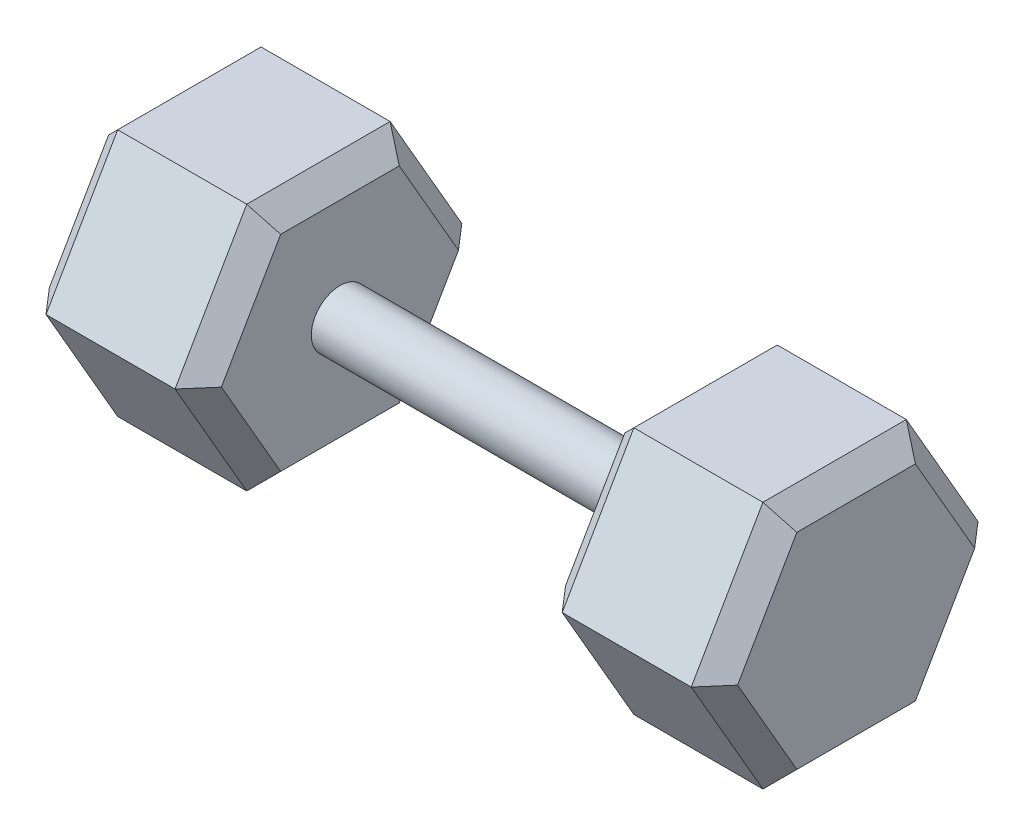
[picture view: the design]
ISO-10303-21;
HEADER;
FILE_DESCRIPTION(('STEP AP214'),'2;1');
FILE_NAME('part.step','',(''),(''),'','','');
FILE_SCHEMA(('AUTOMOTIVE_DESIGN { 1 0 10303 214 1 1 1 1 }'));
ENDSEC;
DATA;
#1=APPLICATION_CONTEXT('core data for automotive mechanical design processes');
#2=APPLICATION_PROTOCOL_DEFINITION('international standard','automotive_design',2000,#1);
#3=PRODUCT_CONTEXT('',#1,'mechanical');
#4=PRODUCT('Part','Part','',(#3));
#5=PRODUCT_RELATED_PRODUCT_CATEGORY('part','',(#4));
#6=PRODUCT_DEFINITION_FORMATION('','',#4);
#7=PRODUCT_DEFINITION_CONTEXT('part definition',#1,'design');
#8=PRODUCT_DEFINITION('design','',#6,#7);
#9=PRODUCT_DEFINITION_SHAPE('','',#8);
#10=(LENGTH_UNIT() NAMED_UNIT(*) SI_UNIT(.MILLI.,.METRE.));
#11=(NAMED_UNIT(*) PLANE_ANGLE_UNIT() SI_UNIT($,.RADIAN.));
#12=(NAMED_UNIT(*) SI_UNIT($,.STERADIAN.) SOLID_ANGLE_UNIT());
#13=UNCERTAINTY_MEASURE_WITH_UNIT(LENGTH_MEASURE(1.E-05),#10,'distance_accuracy_value','');
#14=(GEOMETRIC_REPRESENTATION_CONTEXT(3) GLOBAL_UNCERTAINTY_ASSIGNED_CONTEXT((#13)) GLOBAL_UNIT_ASSIGNED_CONTEXT((#10,
#11,#12)) REPRESENTATION_CONTEXT('',''));
#15=CARTESIAN_POINT('',(0.,0.,0.));
#16=DIRECTION('',(0.,0.,1.));
#17=DIRECTION('',(1.,0.,0.));
#18=AXIS2_PLACEMENT_3D('',#15,#16,#17);
#19=CARTESIAN_POINT('',(76.2,-109.985226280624,0.));
#20=DIRECTION('',(-1.,0.,0.));
#21=DIRECTION('',(0.,0.,1.));
#22=AXIS2_PLACEMENT_3D('',#19,#20,#21);
#23=PLANE('',#22);
#24=DIRECTION('',(0.,-0.866025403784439,-0.5));
#25=VECTOR('',#24,1.);
#26=CARTESIAN_POINT('',(76.2,-105.222726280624,-8.24889197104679));
#27=LINE('',#26,#25);
#28=CARTESIAN_POINT('',(76.2,0.,52.5014773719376));
#29=VERTEX_POINT('',#28);
#30=CARTESIAN_POINT('',(76.2,-45.4676131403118,26.2507386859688));
#31=VERTEX_POINT('',#30);
#32=EDGE_CURVE('E47',#29,#31,#27,.T.);
#33=ORIENTED_EDGE('',*,*,#32,.T.);
#34=DIRECTION('',(0.,0.,-1.));
#35=VECTOR('',#34,1.);
#36=CARTESIAN_POINT('',(76.2,-45.4676131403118,0.));
#37=LINE('',#36,#35);
#38=CARTESIAN_POINT('',(76.2,-45.4676131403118,-26.2507386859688));
#39=VERTEX_POINT('',#38);
#40=EDGE_CURVE('E40',#31,#39,#37,.T.);
#41=ORIENTED_EDGE('',*,*,#40,.T.);
#42=DIRECTION('',(0.,0.866025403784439,-0.5));
#43=VECTOR('',#42,1.);
#44=CARTESIAN_POINT('',(76.2,-105.222726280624,8.24889197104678));
#45=LINE('',#44,#43);
#46=CARTESIAN_POINT('',(76.2,0.,-52.5014773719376));
#47=VERTEX_POINT('',#46);
#48=EDGE_CURVE('E375',#39,#47,#45,.T.);
#49=ORIENTED_EDGE('',*,*,#48,.T.);
#50=DIRECTION('',(0.,0.866025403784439,0.5));
#51=VECTOR('',#50,1.);
#52=CARTESIAN_POINT('',(76.2,-59.7551131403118,-87.0011080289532));
#53=LINE('',#52,#51);
#54=CARTESIAN_POINT('',(76.2,45.4676131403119,-26.2507386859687));
#55=VERTEX_POINT('',#54);
#56=EDGE_CURVE('E377',#47,#55,#53,.T.);
#57=ORIENTED_EDGE('',*,*,#56,.T.);
#58=DIRECTION('',(0.,0.,1.));
#59=VECTOR('',#58,1.);
#60=CARTESIAN_POINT('',(76.2,45.4676131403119,0.));
#61=LINE('',#60,#59);
#62=CARTESIAN_POINT('',(76.2,45.4676131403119,26.2507386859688));
#63=VERTEX_POINT('',#62);
#64=EDGE_CURVE('E379',#55,#63,#61,.T.);
#65=ORIENTED_EDGE('',*,*,#64,.T.);
#66=DIRECTION('',(0.,-0.866025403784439,0.5));
#67=VECTOR('',#66,1.);
#68=CARTESIAN_POINT('',(76.2,-59.7551131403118,87.0011080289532));
#69=LINE('',#68,#67);
#70=EDGE_CURVE('E52',#63,#29,#69,.T.);
#71=ORIENTED_EDGE('',*,*,#70,.T.);
#72=EDGE_LOOP('',(#33,#41,#49,#57,#65,#71));
#73=FACE_BOUND('',#72,.T.);
#74=CARTESIAN_POINT('',(76.2,0.,0.));
#75=DIRECTION('',(-1.,0.,0.));
#76=DIRECTION('',(0.,0.,1.));
#77=AXIS2_PLACEMENT_3D('',#74,#75,#76);
#78=CIRCLE('',#77,12.6913169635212);
#79=CARTESIAN_POINT('',(76.2,0.,12.6913169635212));
#80=VERTEX_POINT('',#79);
#81=EDGE_CURVE('E11',#80,#80,#78,.F.);
#82=ORIENTED_EDGE('',*,*,#81,.F.);
#83=EDGE_LOOP('',(#82));
#84=FACE_BOUND('',#83,.T.);
#85=ADVANCED_FACE('F32',(#73,#84),#23,.F.);
#86=CARTESIAN_POINT('',(76.2,-54.9926131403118,-31.75));
#87=DIRECTION('',(0.,0.5,0.866025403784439));
#88=DIRECTION('',(0.,-0.866025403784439,0.5));
#89=AXIS2_PLACEMENT_3D('',#86,#87,#88);
#90=PLANE('',#89);
#91=DIRECTION('',(-1.,0.,0.));
#92=VECTOR('',#91,1.);
#93=CARTESIAN_POINT('',(76.2,-54.9926131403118,-31.75));
#94=LINE('',#93,#92);
#95=CARTESIAN_POINT('',(66.675,-54.9926131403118,-31.75));
#96=VERTEX_POINT('',#95);
#97=CARTESIAN_POINT('',(9.52500000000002,-54.9926131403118,-31.75));
#98=VERTEX_POINT('',#97);
#99=EDGE_CURVE('E317',#96,#98,#94,.T.);
#100=ORIENTED_EDGE('',*,*,#99,.T.);
#101=DIRECTION('',(0.,0.866025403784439,-0.5));
#102=VECTOR('',#101,1.);
#103=CARTESIAN_POINT('',(9.52499999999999,0.,-63.5));
#104=LINE('',#103,#102);
#105=CARTESIAN_POINT('',(9.52500000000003,0.,-63.5));
#106=VERTEX_POINT('',#105);
#107=EDGE_CURVE('E373',#98,#106,#104,.T.);
#108=ORIENTED_EDGE('',*,*,#107,.T.);
#109=DIRECTION('',(-1.,0.,0.));
#110=VECTOR('',#109,1.);
#111=CARTESIAN_POINT('',(76.2,0.,-63.5));
#112=LINE('',#111,#110);
#113=CARTESIAN_POINT('',(66.675,0.,-63.5));
#114=VERTEX_POINT('',#113);
#115=EDGE_CURVE('E333',#114,#106,#112,.T.);
#116=ORIENTED_EDGE('',*,*,#115,.F.);
#117=DIRECTION('',(0.,-0.866025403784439,0.5));
#118=VECTOR('',#117,1.);
#119=CARTESIAN_POINT('',(66.675,-54.9926131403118,-31.75));
#120=LINE('',#119,#118);
#121=EDGE_CURVE('E371',#114,#96,#120,.T.);
#122=ORIENTED_EDGE('',*,*,#121,.T.);
#123=EDGE_LOOP('',(#100,#108,#116,#122));
#124=FACE_BOUND('',#123,.T.);
#125=ADVANCED_FACE('F474',(#124),#90,.F.);
#126=CARTESIAN_POINT('',(76.2,0.,-63.5));
#127=DIRECTION('',(0.,-0.5,0.866025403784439));
#128=DIRECTION('',(0.,-0.866025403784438,-0.5));
#129=AXIS2_PLACEMENT_3D('',#126,#127,#128);
#130=PLANE('',#129);
#131=ORIENTED_EDGE('',*,*,#115,.T.);
#132=DIRECTION('',(0.,0.866025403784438,0.5));
#133=VECTOR('',#132,1.);
#134=CARTESIAN_POINT('',(9.52499999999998,54.9926131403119,-31.75));
#135=LINE('',#134,#133);
#136=CARTESIAN_POINT('',(9.52500000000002,54.9926131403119,-31.75));
#137=VERTEX_POINT('',#136);
#138=EDGE_CURVE('E338',#106,#137,#135,.T.);
#139=ORIENTED_EDGE('',*,*,#138,.T.);
#140=DIRECTION('',(-1.,0.,0.));
#141=VECTOR('',#140,1.);
#142=CARTESIAN_POINT('',(76.2,54.9926131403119,-31.75));
#143=LINE('',#142,#141);
#144=CARTESIAN_POINT('',(66.675,54.9926131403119,-31.75));
#145=VERTEX_POINT('',#144);
#146=EDGE_CURVE('E330',#145,#137,#143,.T.);
#147=ORIENTED_EDGE('',*,*,#146,.F.);
#148=DIRECTION('',(0.,-0.866025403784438,-0.5));
#149=VECTOR('',#148,1.);
#150=CARTESIAN_POINT('',(66.675,0.,-63.5));
#151=LINE('',#150,#149);
#152=EDGE_CURVE('E336',#145,#114,#151,.T.);
#153=ORIENTED_EDGE('',*,*,#152,.T.);
#154=EDGE_LOOP('',(#131,#139,#147,#153));
#155=FACE_BOUND('',#154,.T.);
#156=ADVANCED_FACE('F426',(#155),#130,.F.);
#157=CARTESIAN_POINT('',(76.2,54.9926131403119,-31.75));
#158=DIRECTION('',(0.,-1.,0.));
#159=DIRECTION('',(0.,0.,-1.));
#160=AXIS2_PLACEMENT_3D('',#157,#158,#159);
#161=PLANE('',#160);
#162=ORIENTED_EDGE('',*,*,#146,.T.);
#163=DIRECTION('',(0.,0.,1.));
#164=VECTOR('',#163,1.);
#165=CARTESIAN_POINT('',(9.52499999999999,54.9926131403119,31.75));
#166=LINE('',#165,#164);
#167=CARTESIAN_POINT('',(9.52500000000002,54.9926131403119,31.75));
#168=VERTEX_POINT('',#167);
#169=EDGE_CURVE('E356',#137,#168,#166,.T.);
#170=ORIENTED_EDGE('',*,*,#169,.T.);
#171=DIRECTION('',(-1.,0.,0.));
#172=VECTOR('',#171,1.);
#173=CARTESIAN_POINT('',(76.2,54.9926131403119,31.75));
#174=LINE('',#173,#172);
#175=CARTESIAN_POINT('',(66.675,54.9926131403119,31.75));
#176=VERTEX_POINT('',#175);
#177=EDGE_CURVE('E327',#176,#168,#174,.T.);
#178=ORIENTED_EDGE('',*,*,#177,.F.);
#179=DIRECTION('',(0.,0.,-1.));
#180=VECTOR('',#179,1.);
#181=CARTESIAN_POINT('',(66.675,54.9926131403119,-31.75));
#182=LINE('',#181,#180);
#183=EDGE_CURVE('E354',#176,#145,#182,.T.);
#184=ORIENTED_EDGE('',*,*,#183,.T.);
#185=EDGE_LOOP('',(#162,#170,#178,#184));
#186=FACE_BOUND('',#185,.T.);
#187=ADVANCED_FACE('F424',(#186),#161,.F.);
#188=CARTESIAN_POINT('',(76.2,54.9926131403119,31.75));
#189=DIRECTION('',(0.,-0.5,-0.866025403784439));
#190=DIRECTION('',(0.,0.866025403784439,-0.5));
#191=AXIS2_PLACEMENT_3D('',#188,#189,#190);
#192=PLANE('',#191);
#193=ORIENTED_EDGE('',*,*,#177,.T.);
#194=DIRECTION('',(0.,-0.866025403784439,0.5));
#195=VECTOR('',#194,1.);
#196=CARTESIAN_POINT('',(9.52499999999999,0.,63.5));
#197=LINE('',#196,#195);
#198=CARTESIAN_POINT('',(9.52500000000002,0.,63.5));
#199=VERTEX_POINT('',#198);
#200=EDGE_CURVE('E360',#168,#199,#197,.T.);
#201=ORIENTED_EDGE('',*,*,#200,.T.);
#202=DIRECTION('',(-1.,0.,0.));
#203=VECTOR('',#202,1.);
#204=CARTESIAN_POINT('',(76.2,0.,63.5));
#205=LINE('',#204,#203);
#206=CARTESIAN_POINT('',(66.675,0.,63.5));
#207=VERTEX_POINT('',#206);
#208=EDGE_CURVE('E324',#207,#199,#205,.T.);
#209=ORIENTED_EDGE('',*,*,#208,.F.);
#210=DIRECTION('',(0.,0.866025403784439,-0.5));
#211=VECTOR('',#210,1.);
#212=CARTESIAN_POINT('',(66.675,54.9926131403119,31.75));
#213=LINE('',#212,#211);
#214=EDGE_CURVE('E358',#207,#176,#213,.T.);
#215=ORIENTED_EDGE('',*,*,#214,.T.);
#216=EDGE_LOOP('',(#193,#201,#209,#215));
#217=FACE_BOUND('',#216,.T.);
#218=ADVANCED_FACE('F442',(#217),#192,.F.);
#219=CARTESIAN_POINT('',(76.2,0.,63.5));
#220=DIRECTION('',(0.,0.5,-0.866025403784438));
#221=DIRECTION('',(0.,0.866025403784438,0.5));
#222=AXIS2_PLACEMENT_3D('',#219,#220,#221);
#223=PLANE('',#222);
#224=ORIENTED_EDGE('',*,*,#208,.T.);
#225=DIRECTION('',(0.,-0.866025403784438,-0.5));
#226=VECTOR('',#225,1.);
#227=CARTESIAN_POINT('',(9.525,-54.9926131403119,31.75));
#228=LINE('',#227,#226);
#229=CARTESIAN_POINT('',(9.52500000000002,-54.9926131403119,31.75));
#230=VERTEX_POINT('',#229);
#231=EDGE_CURVE('E364',#199,#230,#228,.T.);
#232=ORIENTED_EDGE('',*,*,#231,.T.);
#233=DIRECTION('',(-1.,0.,0.));
#234=VECTOR('',#233,1.);
#235=CARTESIAN_POINT('',(76.2,-54.9926131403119,31.75));
#236=LINE('',#235,#234);
#237=CARTESIAN_POINT('',(66.675,-54.9926131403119,31.75));
#238=VERTEX_POINT('',#237);
#239=EDGE_CURVE('E320',#238,#230,#236,.T.);
#240=ORIENTED_EDGE('',*,*,#239,.F.);
#241=DIRECTION('',(0.,0.866025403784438,0.5));
#242=VECTOR('',#241,1.);
#243=CARTESIAN_POINT('',(66.675,0.,63.5));
#244=LINE('',#243,#242);
#245=EDGE_CURVE('E362',#238,#207,#244,.T.);
#246=ORIENTED_EDGE('',*,*,#245,.T.);
#247=EDGE_LOOP('',(#224,#232,#240,#246));
#248=FACE_BOUND('',#247,.T.);
#249=ADVANCED_FACE('F456',(#248),#223,.F.);
#250=CARTESIAN_POINT('',(76.2,-54.9926131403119,31.75));
#251=DIRECTION('',(0.,1.,0.));
#252=DIRECTION('',(0.,0.,1.));
#253=AXIS2_PLACEMENT_3D('',#250,#251,#252);
#254=PLANE('',#253);
#255=ORIENTED_EDGE('',*,*,#239,.T.);
#256=DIRECTION('',(0.,0.,-1.));
#257=VECTOR('',#256,1.);
#258=CARTESIAN_POINT('',(9.52499999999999,-54.9926131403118,-31.75));
#259=LINE('',#258,#257);
#260=EDGE_CURVE('E369',#230,#98,#259,.T.);
#261=ORIENTED_EDGE('',*,*,#260,.T.);
#262=ORIENTED_EDGE('',*,*,#99,.F.);
#263=DIRECTION('',(0.,0.,1.));
#264=VECTOR('',#263,1.);
#265=CARTESIAN_POINT('',(66.675,-54.9926131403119,31.75));
#266=LINE('',#265,#264);
#267=EDGE_CURVE('E366',#96,#238,#266,.T.);
#268=ORIENTED_EDGE('',*,*,#267,.T.);
#269=EDGE_LOOP('',(#255,#261,#262,#268));
#270=FACE_BOUND('',#269,.T.);
#271=ADVANCED_FACE('F458',(#270),#254,.F.);
#272=CARTESIAN_POINT('',(0.,-109.985226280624,0.));
#273=DIRECTION('',(-1.,0.,0.));
#274=DIRECTION('',(0.,0.,1.));
#275=AXIS2_PLACEMENT_3D('',#272,#273,#274);
#276=PLANE('',#275);
#277=DIRECTION('',(0.,0.,-1.));
#278=VECTOR('',#277,1.);
#279=CARTESIAN_POINT('',(0.,45.4676131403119,-31.75));
#280=LINE('',#279,#278);
#281=CARTESIAN_POINT('',(0.,45.4676131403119,26.2507386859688));
#282=VERTEX_POINT('',#281);
#283=CARTESIAN_POINT('',(0.,45.4676131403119,-26.2507386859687));
#284=VERTEX_POINT('',#283);
#285=EDGE_CURVE('E349',#282,#284,#280,.T.);
#286=ORIENTED_EDGE('',*,*,#285,.T.);
#287=DIRECTION('',(0.,-0.866025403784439,-0.5));
#288=VECTOR('',#287,1.);
#289=CARTESIAN_POINT('',(0.,-4.76250000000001,-55.2511080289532));
#290=LINE('',#289,#288);
#291=CARTESIAN_POINT('',(0.,0.,-52.5014773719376));
#292=VERTEX_POINT('',#291);
#293=EDGE_CURVE('E351',#284,#292,#290,.T.);
#294=ORIENTED_EDGE('',*,*,#293,.T.);
#295=DIRECTION('',(0.,-0.866025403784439,0.5));
#296=VECTOR('',#295,1.);
#297=CARTESIAN_POINT('',(0.,-50.2301131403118,-23.5011080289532));
#298=LINE('',#297,#296);
#299=CARTESIAN_POINT('',(0.,-45.4676131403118,-26.2507386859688));
#300=VERTEX_POINT('',#299);
#301=EDGE_CURVE('E341',#292,#300,#298,.T.);
#302=ORIENTED_EDGE('',*,*,#301,.T.);
#303=DIRECTION('',(0.,0.,1.));
#304=VECTOR('',#303,1.);
#305=CARTESIAN_POINT('',(0.,-45.4676131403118,31.75));
#306=LINE('',#305,#304);
#307=CARTESIAN_POINT('',(0.,-45.4676131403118,26.2507386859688));
#308=VERTEX_POINT('',#307);
#309=EDGE_CURVE('E343',#300,#308,#306,.T.);
#310=ORIENTED_EDGE('',*,*,#309,.T.);
#311=DIRECTION('',(0.,0.866025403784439,0.5));
#312=VECTOR('',#311,1.);
#313=CARTESIAN_POINT('',(0.,4.76250000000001,55.2511080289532));
#314=LINE('',#313,#312);
#315=CARTESIAN_POINT('',(0.,0.,52.5014773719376));
#316=VERTEX_POINT('',#315);
#317=EDGE_CURVE('E345',#308,#316,#314,.T.);
#318=ORIENTED_EDGE('',*,*,#317,.T.);
#319=DIRECTION('',(0.,0.866025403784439,-0.5));
#320=VECTOR('',#319,1.);
#321=CARTESIAN_POINT('',(0.,50.2301131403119,23.5011080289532));
#322=LINE('',#321,#320);
#323=EDGE_CURVE('E347',#316,#282,#322,.T.);
#324=ORIENTED_EDGE('',*,*,#323,.T.);
#325=EDGE_LOOP('',(#286,#294,#302,#310,#318,#324));
#326=FACE_BOUND('',#325,.T.);
#327=ADVANCED_FACE('F560',(#326),#276,.T.);
#328=CARTESIAN_POINT('',(9.52499999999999,0.,63.5));
#329=DIRECTION('',(-0.707106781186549,-0.353553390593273,0.612372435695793));
#330=DIRECTION('',(0.654653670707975,0.,0.755928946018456));
#331=AXIS2_PLACEMENT_3D('',#328,#329,#330);
#332=PLANE('',#331);
#333=DIRECTION('',(-0.654653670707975,0.,-0.755928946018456));
#334=VECTOR('',#333,1.);
#335=CARTESIAN_POINT('',(9.52499999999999,0.,63.5));
#336=LINE('',#335,#334);
#337=EDGE_CURVE('E395',#316,#199,#336,.F.);
#338=ORIENTED_EDGE('',*,*,#337,.F.);
#339=ORIENTED_EDGE('',*,*,#317,.F.);
#340=DIRECTION('',(-0.654653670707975,0.654653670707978,-0.377964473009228));
#341=VECTOR('',#340,1.);
#342=CARTESIAN_POINT('',(9.52499999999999,-54.9926131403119,31.75));
#343=LINE('',#342,#341);
#344=EDGE_CURVE('E321',#230,#308,#343,.T.);
#345=ORIENTED_EDGE('',*,*,#344,.F.);
#346=ORIENTED_EDGE('',*,*,#231,.F.);
#347=EDGE_LOOP('',(#338,#339,#345,#346));
#348=FACE_BOUND('',#347,.T.);
#349=ADVANCED_FACE('F451',(#348),#332,.T.);
#350=CARTESIAN_POINT('',(9.52499999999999,-54.9926131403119,31.75));
#351=DIRECTION('',(-0.707106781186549,-0.707106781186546,0.));
#352=DIRECTION('',(0.707106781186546,-0.707106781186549,0.));
#353=AXIS2_PLACEMENT_3D('',#350,#351,#352);
#354=PLANE('',#353);
#355=ORIENTED_EDGE('',*,*,#344,.T.);
#356=ORIENTED_EDGE('',*,*,#309,.F.);
#357=DIRECTION('',(-0.654653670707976,0.654653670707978,0.377964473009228));
#358=VECTOR('',#357,1.);
#359=CARTESIAN_POINT('',(9.52499999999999,-54.9926131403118,-31.75));
#360=LINE('',#359,#358);
#361=EDGE_CURVE('E392',#98,#300,#360,.T.);
#362=ORIENTED_EDGE('',*,*,#361,.F.);
#363=ORIENTED_EDGE('',*,*,#260,.F.);
#364=EDGE_LOOP('',(#355,#356,#362,#363));
#365=FACE_BOUND('',#364,.T.);
#366=ADVANCED_FACE('F587',(#365),#354,.T.);
#367=CARTESIAN_POINT('',(9.52499999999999,54.9926131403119,31.75));
#368=DIRECTION('',(-0.707106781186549,0.353553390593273,0.612372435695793));
#369=DIRECTION('',(0.654653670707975,0.,0.755928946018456));
#370=AXIS2_PLACEMENT_3D('',#367,#368,#369);
#371=PLANE('',#370);
#372=ORIENTED_EDGE('',*,*,#337,.T.);
#373=ORIENTED_EDGE('',*,*,#200,.F.);
#374=DIRECTION('',(-0.654653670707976,-0.654653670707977,-0.37796447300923));
#375=VECTOR('',#374,1.);
#376=CARTESIAN_POINT('',(9.52499999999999,54.9926131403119,31.75));
#377=LINE('',#376,#375);
#378=EDGE_CURVE('E389',#282,#168,#377,.F.);
#379=ORIENTED_EDGE('',*,*,#378,.F.);
#380=ORIENTED_EDGE('',*,*,#323,.F.);
#381=EDGE_LOOP('',(#372,#373,#379,#380));
#382=FACE_BOUND('',#381,.T.);
#383=ADVANCED_FACE('F445',(#382),#371,.T.);
#384=CARTESIAN_POINT('',(9.52499999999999,-54.9926131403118,-31.75));
#385=DIRECTION('',(-0.707106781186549,-0.353553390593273,-0.612372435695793));
#386=DIRECTION('',(-0.654653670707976,0.,0.755928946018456));
#387=AXIS2_PLACEMENT_3D('',#384,#385,#386);
#388=PLANE('',#387);
#389=ORIENTED_EDGE('',*,*,#361,.T.);
#390=ORIENTED_EDGE('',*,*,#301,.F.);
#391=DIRECTION('',(0.654653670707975,0.,-0.755928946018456));
#392=VECTOR('',#391,1.);
#393=CARTESIAN_POINT('',(-6.18717518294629,0.,-45.3571428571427));
#394=LINE('',#393,#392);
#395=EDGE_CURVE('E386',#106,#292,#394,.F.);
#396=ORIENTED_EDGE('',*,*,#395,.F.);
#397=ORIENTED_EDGE('',*,*,#107,.F.);
#398=EDGE_LOOP('',(#389,#390,#396,#397));
#399=FACE_BOUND('',#398,.T.);
#400=ADVANCED_FACE('F581',(#399),#388,.T.);
#401=CARTESIAN_POINT('',(9.52499999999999,54.9926131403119,-31.75));
#402=DIRECTION('',(-0.707106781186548,0.707106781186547,0.));
#403=DIRECTION('',(-0.707106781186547,-0.707106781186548,0.));
#404=AXIS2_PLACEMENT_3D('',#401,#402,#403);
#405=PLANE('',#404);
#406=ORIENTED_EDGE('',*,*,#378,.T.);
#407=ORIENTED_EDGE('',*,*,#169,.F.);
#408=DIRECTION('',(-0.654653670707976,-0.654653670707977,0.37796447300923));
#409=VECTOR('',#408,1.);
#410=CARTESIAN_POINT('',(9.52499999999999,54.9926131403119,-31.75));
#411=LINE('',#410,#409);
#412=EDGE_CURVE('E384',#284,#137,#411,.F.);
#413=ORIENTED_EDGE('',*,*,#412,.F.);
#414=ORIENTED_EDGE('',*,*,#285,.F.);
#415=EDGE_LOOP('',(#406,#407,#413,#414));
#416=FACE_BOUND('',#415,.T.);
#417=ADVANCED_FACE('F438',(#416),#405,.T.);
#418=CARTESIAN_POINT('',(9.52499999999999,0.,-63.5));
#419=DIRECTION('',(-0.70710678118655,0.353553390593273,-0.612372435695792));
#420=DIRECTION('',(-0.654653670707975,0.,0.755928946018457));
#421=AXIS2_PLACEMENT_3D('',#418,#419,#420);
#422=PLANE('',#421);
#423=ORIENTED_EDGE('',*,*,#395,.T.);
#424=ORIENTED_EDGE('',*,*,#293,.F.);
#425=ORIENTED_EDGE('',*,*,#412,.T.);
#426=ORIENTED_EDGE('',*,*,#138,.F.);
#427=EDGE_LOOP('',(#423,#424,#425,#426));
#428=FACE_BOUND('',#427,.T.);
#429=ADVANCED_FACE('F431',(#428),#422,.T.);
#430=CARTESIAN_POINT('',(76.2,45.4676131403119,0.));
#431=DIRECTION('',(-0.707106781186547,-0.707106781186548,0.));
#432=DIRECTION('',(0.707106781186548,-0.707106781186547,0.));
#433=AXIS2_PLACEMENT_3D('',#430,#431,#432);
#434=PLANE('',#433);
#435=DIRECTION('',(0.654653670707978,-0.654653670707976,0.377964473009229));
#436=VECTOR('',#435,1.);
#437=CARTESIAN_POINT('',(106.263636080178,15.4039770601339,-8.89349030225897));
#438=LINE('',#437,#436);
#439=EDGE_CURVE('E409',#145,#55,#438,.T.);
#440=ORIENTED_EDGE('',*,*,#439,.F.);
#441=ORIENTED_EDGE('',*,*,#183,.F.);
#442=DIRECTION('',(0.654653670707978,-0.654653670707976,-0.377964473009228));
#443=VECTOR('',#442,1.);
#444=CARTESIAN_POINT('',(82.6953733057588,38.972239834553,22.5006331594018));
#445=LINE('',#444,#443);
#446=EDGE_CURVE('E387',#63,#176,#445,.F.);
#447=ORIENTED_EDGE('',*,*,#446,.F.);
#448=ORIENTED_EDGE('',*,*,#64,.F.);
#449=EDGE_LOOP('',(#440,#441,#447,#448));
#450=FACE_BOUND('',#449,.T.);
#451=ADVANCED_FACE('F34',(#450),#434,.F.);
#452=CARTESIAN_POINT('',(76.2,-59.7551131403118,87.0011080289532));
#453=DIRECTION('',(-0.707106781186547,-0.353553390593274,-0.612372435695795));
#454=DIRECTION('',(-0.654653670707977,0.,0.755928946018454));
#455=AXIS2_PLACEMENT_3D('',#452,#453,#454);
#456=PLANE('',#455);
#457=ORIENTED_EDGE('',*,*,#446,.T.);
#458=ORIENTED_EDGE('',*,*,#214,.F.);
#459=DIRECTION('',(0.654653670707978,0.,-0.755928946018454));
#460=VECTOR('',#459,1.);
#461=CARTESIAN_POINT('',(59.1271105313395,0.,72.2155520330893));
#462=LINE('',#461,#460);
#463=EDGE_CURVE('E406',#29,#207,#462,.F.);
#464=ORIENTED_EDGE('',*,*,#463,.F.);
#465=ORIENTED_EDGE('',*,*,#70,.F.);
#466=EDGE_LOOP('',(#457,#458,#464,#465));
#467=FACE_BOUND('',#466,.T.);
#468=ADVANCED_FACE('F415',(#467),#456,.F.);
#469=CARTESIAN_POINT('',(76.2,-59.7551131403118,-87.0011080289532));
#470=DIRECTION('',(-0.707106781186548,-0.353553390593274,0.612372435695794));
#471=DIRECTION('',(0.654653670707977,0.,0.755928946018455));
#472=AXIS2_PLACEMENT_3D('',#469,#470,#471);
#473=PLANE('',#472);
#474=ORIENTED_EDGE('',*,*,#439,.T.);
#475=ORIENTED_EDGE('',*,*,#56,.F.);
#476=DIRECTION('',(0.654653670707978,0.,0.755928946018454));
#477=VECTOR('',#476,1.);
#478=CARTESIAN_POINT('',(106.263636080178,0.,-17.7869806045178));
#479=LINE('',#478,#477);
#480=EDGE_CURVE('E403',#114,#47,#479,.T.);
#481=ORIENTED_EDGE('',*,*,#480,.F.);
#482=ORIENTED_EDGE('',*,*,#152,.F.);
#483=EDGE_LOOP('',(#474,#475,#481,#482));
#484=FACE_BOUND('',#483,.T.);
#485=ADVANCED_FACE('F600',(#484),#473,.F.);
#486=CARTESIAN_POINT('',(76.2,-105.222726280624,-8.2488919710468));
#487=DIRECTION('',(-0.707106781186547,0.353553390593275,-0.612372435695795));
#488=DIRECTION('',(-0.654653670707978,0.,0.755928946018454));
#489=AXIS2_PLACEMENT_3D('',#486,#487,#488);
#490=PLANE('',#489);
#491=ORIENTED_EDGE('',*,*,#463,.T.);
#492=ORIENTED_EDGE('',*,*,#245,.F.);
#493=DIRECTION('',(0.654653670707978,0.654653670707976,-0.377964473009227));
#494=VECTOR('',#493,1.);
#495=CARTESIAN_POINT('',(59.1271105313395,-62.5405026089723,36.1077760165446));
#496=LINE('',#495,#494);
#497=EDGE_CURVE('E401',#31,#238,#496,.F.);
#498=ORIENTED_EDGE('',*,*,#497,.F.);
#499=ORIENTED_EDGE('',*,*,#32,.F.);
#500=EDGE_LOOP('',(#491,#492,#498,#499));
#501=FACE_BOUND('',#500,.T.);
#502=ADVANCED_FACE('F597',(#501),#490,.F.);
#503=CARTESIAN_POINT('',(76.2,-105.222726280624,8.24889197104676));
#504=DIRECTION('',(-0.707106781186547,0.353553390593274,0.612372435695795));
#505=DIRECTION('',(0.654653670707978,0.,0.755928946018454));
#506=AXIS2_PLACEMENT_3D('',#503,#504,#505);
#507=PLANE('',#506);
#508=ORIENTED_EDGE('',*,*,#480,.T.);
#509=ORIENTED_EDGE('',*,*,#48,.F.);
#510=DIRECTION('',(-0.654653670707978,-0.654653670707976,-0.377964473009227));
#511=VECTOR('',#510,1.);
#512=CARTESIAN_POINT('',(59.1271105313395,-62.5405026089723,-36.1077760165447));
#513=LINE('',#512,#511);
#514=EDGE_CURVE('E316',#96,#39,#513,.F.);
#515=ORIENTED_EDGE('',*,*,#514,.F.);
#516=ORIENTED_EDGE('',*,*,#121,.F.);
#517=EDGE_LOOP('',(#508,#509,#515,#516));
#518=FACE_BOUND('',#517,.T.);
#519=ADVANCED_FACE('F469',(#518),#507,.F.);
#520=CARTESIAN_POINT('',(76.2,-45.4676131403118,0.));
#521=DIRECTION('',(-0.707106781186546,0.707106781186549,0.));
#522=DIRECTION('',(-0.707106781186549,-0.707106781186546,0.));
#523=AXIS2_PLACEMENT_3D('',#520,#521,#522);
#524=PLANE('',#523);
#525=ORIENTED_EDGE('',*,*,#497,.T.);
#526=ORIENTED_EDGE('',*,*,#267,.F.);
#527=ORIENTED_EDGE('',*,*,#514,.T.);
#528=ORIENTED_EDGE('',*,*,#40,.F.);
#529=EDGE_LOOP('',(#525,#526,#527,#528));
#530=FACE_BOUND('',#529,.T.);
#531=ADVANCED_FACE('F463',(#530),#524,.F.);
#532=CARTESIAN_POINT('',(152.4,0.,0.));
#533=DIRECTION('',(-1.,0.,0.));
#534=DIRECTION('',(0.,0.,1.));
#535=AXIS2_PLACEMENT_3D('',#532,#533,#534);
#536=CYLINDRICAL_SURFACE('',#535,12.6913169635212);
#537=CARTESIAN_POINT('',(228.6,0.,0.));
#538=DIRECTION('',(-1.,0.,0.));
#539=DIRECTION('',(0.,0.,1.));
#540=AXIS2_PLACEMENT_3D('',#537,#538,#539);
#541=CIRCLE('',#540,12.6913169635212);
#542=CARTESIAN_POINT('',(228.6,0.,12.6913169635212));
#543=VERTEX_POINT('',#542);
#544=EDGE_CURVE('E292',#543,#543,#541,.F.);
#545=CARTESIAN_POINT('',(76.2,0.,12.6913169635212));
#546=CARTESIAN_POINT('',(77.7875,0.,12.6913169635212));
#547=CARTESIAN_POINT('',(79.375,0.,12.6913169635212));
#548=CARTESIAN_POINT('',(82.55,0.,12.6913169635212));
#549=CARTESIAN_POINT('',(84.1375,0.,12.6913169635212));
#550=CARTESIAN_POINT('',(87.3125,0.,12.6913169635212));
#551=CARTESIAN_POINT('',(88.9,0.,12.6913169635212));
#552=CARTESIAN_POINT('',(92.075,0.,12.6913169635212));
#553=CARTESIAN_POINT('',(93.6625,0.,12.6913169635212));
#554=CARTESIAN_POINT('',(96.8375,0.,12.6913169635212));
#555=CARTESIAN_POINT('',(98.425,0.,12.6913169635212));
#556=CARTESIAN_POINT('',(101.6,0.,12.6913169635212));
#557=CARTESIAN_POINT('',(103.1875,0.,12.6913169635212));
#558=CARTESIAN_POINT('',(106.3625,0.,12.6913169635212));
#559=CARTESIAN_POINT('',(107.95,0.,12.6913169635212));
#560=CARTESIAN_POINT('',(111.125,0.,12.6913169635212));
#561=CARTESIAN_POINT('',(112.7125,0.,12.6913169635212));
#562=CARTESIAN_POINT('',(115.8875,0.,12.6913169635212));
#563=CARTESIAN_POINT('',(117.475,0.,12.6913169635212));
#564=CARTESIAN_POINT('',(120.65,0.,12.6913169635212));
#565=CARTESIAN_POINT('',(122.2375,0.,12.6913169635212));
#566=CARTESIAN_POINT('',(125.4125,0.,12.6913169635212));
#567=CARTESIAN_POINT('',(127.,0.,12.6913169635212));
#568=CARTESIAN_POINT('',(130.175,0.,12.6913169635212));
#569=CARTESIAN_POINT('',(131.7625,0.,12.6913169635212));
#570=CARTESIAN_POINT('',(134.9375,0.,12.6913169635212));
#571=CARTESIAN_POINT('',(136.525,0.,12.6913169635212));
#572=CARTESIAN_POINT('',(139.7,0.,12.6913169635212));
#573=CARTESIAN_POINT('',(141.2875,0.,12.6913169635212));
#574=CARTESIAN_POINT('',(144.4625,0.,12.6913169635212));
#575=CARTESIAN_POINT('',(146.05,0.,12.6913169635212));
#576=CARTESIAN_POINT('',(149.225,0.,12.6913169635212));
#577=CARTESIAN_POINT('',(150.8125,0.,12.6913169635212));
#578=CARTESIAN_POINT('',(153.9875,0.,12.6913169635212));
#579=CARTESIAN_POINT('',(155.575,0.,12.6913169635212));
#580=CARTESIAN_POINT('',(158.75,0.,12.6913169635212));
#581=CARTESIAN_POINT('',(160.3375,0.,12.6913169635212));
#582=CARTESIAN_POINT('',(163.5125,0.,12.6913169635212));
#583=CARTESIAN_POINT('',(165.1,0.,12.6913169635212));
#584=CARTESIAN_POINT('',(168.275,0.,12.6913169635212));
#585=CARTESIAN_POINT('',(169.8625,0.,12.6913169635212));
#586=CARTESIAN_POINT('',(173.0375,0.,12.6913169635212));
#587=CARTESIAN_POINT('',(174.625,0.,12.6913169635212));
#588=CARTESIAN_POINT('',(177.8,0.,12.6913169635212));
#589=CARTESIAN_POINT('',(179.3875,0.,12.6913169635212));
#590=CARTESIAN_POINT('',(182.5625,0.,12.6913169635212));
#591=CARTESIAN_POINT('',(184.15,0.,12.6913169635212));
#592=CARTESIAN_POINT('',(187.325,0.,12.6913169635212));
#593=CARTESIAN_POINT('',(188.9125,0.,12.6913169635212));
#594=CARTESIAN_POINT('',(192.0875,0.,12.6913169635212));
#595=CARTESIAN_POINT('',(193.675,0.,12.6913169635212));
#596=CARTESIAN_POINT('',(196.85,0.,12.6913169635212));
#597=CARTESIAN_POINT('',(198.4375,0.,12.6913169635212));
#598=CARTESIAN_POINT('',(201.6125,0.,12.6913169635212));
#599=CARTESIAN_POINT('',(203.2,0.,12.6913169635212));
#600=CARTESIAN_POINT('',(206.375,0.,12.6913169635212));
#601=CARTESIAN_POINT('',(207.9625,0.,12.6913169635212));
#602=CARTESIAN_POINT('',(211.1375,0.,12.6913169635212));
#603=CARTESIAN_POINT('',(212.725,0.,12.6913169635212));
#604=CARTESIAN_POINT('',(215.9,0.,12.6913169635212));
#605=CARTESIAN_POINT('',(217.4875,0.,12.6913169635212));
#606=CARTESIAN_POINT('',(220.6625,0.,12.6913169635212));
#607=CARTESIAN_POINT('',(222.25,0.,12.6913169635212));
#608=CARTESIAN_POINT('',(225.425,0.,12.6913169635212));
#609=CARTESIAN_POINT('',(227.0125,0.,12.6913169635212));
#610=CARTESIAN_POINT('',(228.6,0.,12.6913169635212));
#611=B_SPLINE_CURVE_WITH_KNOTS('',3,(#545,#546,#547,#548,#549,#550,#551,#552,#553,#554,#555,
#556,#557,#558,#559,#560,#561,#562,#563,#564,#565,#566,#567,#568,#569,#570,#571,#572,#573,#574,
#575,#576,#577,#578,#579,#580,#581,#582,#583,#584,#585,#586,#587,#588,#589,#590,#591,#592,#593,
#594,#595,#596,#597,#598,#599,#600,#601,#602,#603,#604,#605,#606,#607,#608,#609,#610),
.UNSPECIFIED.,.F.,.F.,(4,2,2,2,2,2,2,2,2,2,2,2,2,2,2,2,2,2,2,2,2,2,2,2,2,2,2,2,2,2,2,2,4),(0.,
4.7625,9.52500000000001,14.2875,19.05,23.8125,28.575,33.3375,38.1,42.8625,47.625,52.3875,57.15,
61.9125,66.675,71.4375,76.2,80.9625,85.725,90.4875,95.25,100.0125,104.775,109.5375,114.3,
119.0625,123.825,128.5875,133.35,138.1125,142.875,147.6375,152.4),.UNSPECIFIED.);
#612=EDGE_CURVE('BSEAM478',#80,#543,#611,.T.);
#613=ORIENTED_EDGE('',*,*,#81,.T.);
#614=ORIENTED_EDGE('',*,*,#544,.F.);
#615=ORIENTED_EDGE('',*,*,#612,.T.);
#616=ORIENTED_EDGE('',*,*,#612,.F.);
#617=EDGE_LOOP('',(#613,#615,#614,#616));
#618=FACE_BOUND('',#617,.T.);
#619=ADVANCED_FACE('F478',(#618),#536,.T.);
#620=CARTESIAN_POINT('',(228.6,-109.985226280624,0.));
#621=DIRECTION('',(1.,0.,0.));
#622=DIRECTION('',(0.,0.,1.));
#623=AXIS2_PLACEMENT_3D('',#620,#621,#622);
#624=PLANE('',#623);
#625=DIRECTION('',(0.,-0.866025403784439,-0.5));
#626=VECTOR('',#625,1.);
#627=CARTESIAN_POINT('',(228.6,-105.222726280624,-8.24889197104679));
#628=LINE('',#627,#626);
#629=CARTESIAN_POINT('',(228.6,0.,52.5014773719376));
#630=VERTEX_POINT('',#629);
#631=CARTESIAN_POINT('',(228.6,-45.4676131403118,26.2507386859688));
#632=VERTEX_POINT('',#631);
#633=EDGE_CURVE('E286',#630,#632,#628,.T.);
#634=ORIENTED_EDGE('',*,*,#633,.F.);
#635=DIRECTION('',(0.,-0.866025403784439,0.5));
#636=VECTOR('',#635,1.);
#637=CARTESIAN_POINT('',(228.6,-59.7551131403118,87.0011080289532));
#638=LINE('',#637,#636);
#639=CARTESIAN_POINT('',(228.6,45.4676131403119,26.2507386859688));
#640=VERTEX_POINT('',#639);
#641=EDGE_CURVE('E283',#640,#630,#638,.T.);
#642=ORIENTED_EDGE('',*,*,#641,.F.);
#643=DIRECTION('',(0.,0.,1.));
#644=VECTOR('',#643,1.);
#645=CARTESIAN_POINT('',(228.6,45.4676131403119,0.));
#646=LINE('',#645,#644);
#647=CARTESIAN_POINT('',(228.6,45.4676131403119,-26.2507386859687));
#648=VERTEX_POINT('',#647);
#649=EDGE_CURVE('E281',#648,#640,#646,.T.);
#650=ORIENTED_EDGE('',*,*,#649,.F.);
#651=DIRECTION('',(0.,0.866025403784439,0.5));
#652=VECTOR('',#651,1.);
#653=CARTESIAN_POINT('',(228.6,-59.7551131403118,-87.0011080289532));
#654=LINE('',#653,#652);
#655=CARTESIAN_POINT('',(228.6,0.,-52.5014773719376));
#656=VERTEX_POINT('',#655);
#657=EDGE_CURVE('E200',#656,#648,#654,.T.);
#658=ORIENTED_EDGE('',*,*,#657,.F.);
#659=DIRECTION('',(0.,0.866025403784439,-0.5));
#660=VECTOR('',#659,1.);
#661=CARTESIAN_POINT('',(228.6,-105.222726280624,8.24889197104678));
#662=LINE('',#661,#660);
#663=CARTESIAN_POINT('',(228.6,-45.4676131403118,-26.2507386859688));
#664=VERTEX_POINT('',#663);
#665=EDGE_CURVE('E277',#664,#656,#662,.T.);
#666=ORIENTED_EDGE('',*,*,#665,.F.);
#667=DIRECTION('',(0.,0.,-1.));
#668=VECTOR('',#667,1.);
#669=CARTESIAN_POINT('',(228.6,-45.4676131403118,0.));
#670=LINE('',#669,#668);
#671=EDGE_CURVE('E289',#632,#664,#670,.T.);
#672=ORIENTED_EDGE('',*,*,#671,.F.);
#673=EDGE_LOOP('',(#634,#642,#650,#658,#666,#672));
#674=FACE_BOUND('',#673,.T.);
#675=ORIENTED_EDGE('',*,*,#544,.T.);
#676=EDGE_LOOP('',(#675));
#677=FACE_BOUND('',#676,.T.);
#678=ADVANCED_FACE('F481',(#674,#677),#624,.F.);
#679=CARTESIAN_POINT('',(228.6,-54.9926131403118,-31.75));
#680=DIRECTION('',(0.,0.5,0.866025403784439));
#681=DIRECTION('',(0.,-0.866025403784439,0.5));
#682=AXIS2_PLACEMENT_3D('',#679,#680,#681);
#683=PLANE('',#682);
#684=DIRECTION('',(1.,0.,0.));
#685=VECTOR('',#684,1.);
#686=CARTESIAN_POINT('',(228.6,-54.9926131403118,-31.75));
#687=LINE('',#686,#685);
#688=CARTESIAN_POINT('',(238.125,-54.9926131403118,-31.75));
#689=VERTEX_POINT('',#688);
#690=CARTESIAN_POINT('',(295.275,-54.9926131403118,-31.75));
#691=VERTEX_POINT('',#690);
#692=EDGE_CURVE('E305',#689,#691,#687,.T.);
#693=ORIENTED_EDGE('',*,*,#692,.F.);
#694=DIRECTION('',(0.,-0.866025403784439,0.5));
#695=VECTOR('',#694,1.);
#696=CARTESIAN_POINT('',(238.125,-54.9926131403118,-31.75));
#697=LINE('',#696,#695);
#698=CARTESIAN_POINT('',(238.125,0.,-63.5));
#699=VERTEX_POINT('',#698);
#700=EDGE_CURVE('E271',#699,#689,#697,.T.);
#701=ORIENTED_EDGE('',*,*,#700,.F.);
#702=DIRECTION('',(1.,0.,0.));
#703=VECTOR('',#702,1.);
#704=CARTESIAN_POINT('',(228.6,0.,-63.5));
#705=LINE('',#704,#703);
#706=CARTESIAN_POINT('',(295.275,0.,-63.5));
#707=VERTEX_POINT('',#706);
#708=EDGE_CURVE('E225',#699,#707,#705,.T.);
#709=ORIENTED_EDGE('',*,*,#708,.T.);
#710=DIRECTION('',(0.,0.866025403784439,-0.5));
#711=VECTOR('',#710,1.);
#712=CARTESIAN_POINT('',(295.275,0.,-63.5));
#713=LINE('',#712,#711);
#714=EDGE_CURVE('E274',#691,#707,#713,.T.);
#715=ORIENTED_EDGE('',*,*,#714,.F.);
#716=EDGE_LOOP('',(#693,#701,#709,#715));
#717=FACE_BOUND('',#716,.T.);
#718=ADVANCED_FACE('F486',(#717),#683,.F.);
#719=CARTESIAN_POINT('',(228.6,0.,-63.5));
#720=DIRECTION('',(0.,-0.5,0.866025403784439));
#721=DIRECTION('',(0.,-0.866025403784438,-0.5));
#722=AXIS2_PLACEMENT_3D('',#719,#720,#721);
#723=PLANE('',#722);
#724=ORIENTED_EDGE('',*,*,#708,.F.);
#725=DIRECTION('',(0.,-0.866025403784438,-0.5));
#726=VECTOR('',#725,1.);
#727=CARTESIAN_POINT('',(238.125,0.,-63.5));
#728=LINE('',#727,#726);
#729=CARTESIAN_POINT('',(238.125,54.9926131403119,-31.75));
#730=VERTEX_POINT('',#729);
#731=EDGE_CURVE('E197',#730,#699,#728,.T.);
#732=ORIENTED_EDGE('',*,*,#731,.F.);
#733=DIRECTION('',(1.,0.,0.));
#734=VECTOR('',#733,1.);
#735=CARTESIAN_POINT('',(228.6,54.9926131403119,-31.75));
#736=LINE('',#735,#734);
#737=CARTESIAN_POINT('',(295.275,54.9926131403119,-31.75));
#738=VERTEX_POINT('',#737);
#739=EDGE_CURVE('E219',#730,#738,#736,.T.);
#740=ORIENTED_EDGE('',*,*,#739,.T.);
#741=DIRECTION('',(0.,0.866025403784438,0.5));
#742=VECTOR('',#741,1.);
#743=CARTESIAN_POINT('',(295.275,54.9926131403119,-31.75));
#744=LINE('',#743,#742);
#745=EDGE_CURVE('E231',#707,#738,#744,.T.);
#746=ORIENTED_EDGE('',*,*,#745,.F.);
#747=EDGE_LOOP('',(#724,#732,#740,#746));
#748=FACE_BOUND('',#747,.T.);
#749=ADVANCED_FACE('F228',(#748),#723,.F.);
#750=CARTESIAN_POINT('',(228.6,54.9926131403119,-31.75));
#751=DIRECTION('',(0.,-1.,0.));
#752=DIRECTION('',(0.,0.,-1.));
#753=AXIS2_PLACEMENT_3D('',#750,#751,#752);
#754=PLANE('',#753);
#755=ORIENTED_EDGE('',*,*,#739,.F.);
#756=DIRECTION('',(0.,0.,-1.));
#757=VECTOR('',#756,1.);
#758=CARTESIAN_POINT('',(238.125,54.9926131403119,-31.75));
#759=LINE('',#758,#757);
#760=CARTESIAN_POINT('',(238.125,54.9926131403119,31.75));
#761=VERTEX_POINT('',#760);
#762=EDGE_CURVE('E208',#761,#730,#759,.T.);
#763=ORIENTED_EDGE('',*,*,#762,.F.);
#764=DIRECTION('',(1.,0.,0.));
#765=VECTOR('',#764,1.);
#766=CARTESIAN_POINT('',(228.6,54.9926131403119,31.75));
#767=LINE('',#766,#765);
#768=CARTESIAN_POINT('',(295.275,54.9926131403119,31.75));
#769=VERTEX_POINT('',#768);
#770=EDGE_CURVE('E226',#761,#769,#767,.T.);
#771=ORIENTED_EDGE('',*,*,#770,.T.);
#772=DIRECTION('',(0.,0.,1.));
#773=VECTOR('',#772,1.);
#774=CARTESIAN_POINT('',(295.275,54.9926131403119,31.75));
#775=LINE('',#774,#773);
#776=EDGE_CURVE('E214',#738,#769,#775,.T.);
#777=ORIENTED_EDGE('',*,*,#776,.F.);
#778=EDGE_LOOP('',(#755,#763,#771,#777));
#779=FACE_BOUND('',#778,.T.);
#780=ADVANCED_FACE('F220',(#779),#754,.F.);
#781=CARTESIAN_POINT('',(228.6,54.9926131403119,31.75));
#782=DIRECTION('',(0.,-0.5,-0.866025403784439));
#783=DIRECTION('',(0.,0.866025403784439,-0.5));
#784=AXIS2_PLACEMENT_3D('',#781,#782,#783);
#785=PLANE('',#784);
#786=ORIENTED_EDGE('',*,*,#770,.F.);
#787=DIRECTION('',(0.,0.866025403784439,-0.5));
#788=VECTOR('',#787,1.);
#789=CARTESIAN_POINT('',(238.125,54.9926131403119,31.75));
#790=LINE('',#789,#788);
#791=CARTESIAN_POINT('',(238.125,0.,63.5));
#792=VERTEX_POINT('',#791);
#793=EDGE_CURVE('E254',#792,#761,#790,.T.);
#794=ORIENTED_EDGE('',*,*,#793,.F.);
#795=DIRECTION('',(1.,0.,0.));
#796=VECTOR('',#795,1.);
#797=CARTESIAN_POINT('',(228.6,0.,63.5));
#798=LINE('',#797,#796);
#799=CARTESIAN_POINT('',(295.275,0.,63.5));
#800=VERTEX_POINT('',#799);
#801=EDGE_CURVE('E866',#792,#800,#798,.T.);
#802=ORIENTED_EDGE('',*,*,#801,.T.);
#803=DIRECTION('',(0.,-0.866025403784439,0.5));
#804=VECTOR('',#803,1.);
#805=CARTESIAN_POINT('',(295.275,0.,63.5));
#806=LINE('',#805,#804);
#807=EDGE_CURVE('E256',#769,#800,#806,.T.);
#808=ORIENTED_EDGE('',*,*,#807,.F.);
#809=EDGE_LOOP('',(#786,#794,#802,#808));
#810=FACE_BOUND('',#809,.T.);
#811=ADVANCED_FACE('F508',(#810),#785,.F.);
#812=CARTESIAN_POINT('',(228.6,0.,63.5));
#813=DIRECTION('',(0.,0.5,-0.866025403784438));
#814=DIRECTION('',(0.,0.866025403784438,0.5));
#815=AXIS2_PLACEMENT_3D('',#812,#813,#814);
#816=PLANE('',#815);
#817=ORIENTED_EDGE('',*,*,#801,.F.);
#818=DIRECTION('',(0.,0.866025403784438,0.5));
#819=VECTOR('',#818,1.);
#820=CARTESIAN_POINT('',(238.125,0.,63.5));
#821=LINE('',#820,#819);
#822=CARTESIAN_POINT('',(238.125,-54.9926131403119,31.75));
#823=VERTEX_POINT('',#822);
#824=EDGE_CURVE('E259',#823,#792,#821,.T.);
#825=ORIENTED_EDGE('',*,*,#824,.F.);
#826=DIRECTION('',(1.,0.,0.));
#827=VECTOR('',#826,1.);
#828=CARTESIAN_POINT('',(228.6,-54.9926131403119,31.75));
#829=LINE('',#828,#827);
#830=CARTESIAN_POINT('',(295.275,-54.9926131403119,31.75));
#831=VERTEX_POINT('',#830);
#832=EDGE_CURVE('E868',#823,#831,#829,.T.);
#833=ORIENTED_EDGE('',*,*,#832,.T.);
#834=DIRECTION('',(0.,-0.866025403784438,-0.5));
#835=VECTOR('',#834,1.);
#836=CARTESIAN_POINT('',(295.275,-54.9926131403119,31.75));
#837=LINE('',#836,#835);
#838=EDGE_CURVE('E262',#800,#831,#837,.T.);
#839=ORIENTED_EDGE('',*,*,#838,.F.);
#840=EDGE_LOOP('',(#817,#825,#833,#839));
#841=FACE_BOUND('',#840,.T.);
#842=ADVANCED_FACE('F504',(#841),#816,.F.);
#843=CARTESIAN_POINT('',(228.6,-54.9926131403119,31.75));
#844=DIRECTION('',(0.,1.,0.));
#845=DIRECTION('',(0.,0.,1.));
#846=AXIS2_PLACEMENT_3D('',#843,#844,#845);
#847=PLANE('',#846);
#848=ORIENTED_EDGE('',*,*,#832,.F.);
#849=DIRECTION('',(0.,0.,1.));
#850=VECTOR('',#849,1.);
#851=CARTESIAN_POINT('',(238.125,-54.9926131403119,31.75));
#852=LINE('',#851,#850);
#853=EDGE_CURVE('E265',#689,#823,#852,.T.);
#854=ORIENTED_EDGE('',*,*,#853,.F.);
#855=ORIENTED_EDGE('',*,*,#692,.T.);
#856=DIRECTION('',(0.,0.,-1.));
#857=VECTOR('',#856,1.);
#858=CARTESIAN_POINT('',(295.275,-54.9926131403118,-31.75));
#859=LINE('',#858,#857);
#860=EDGE_CURVE('E268',#831,#691,#859,.T.);
#861=ORIENTED_EDGE('',*,*,#860,.F.);
#862=EDGE_LOOP('',(#848,#854,#855,#861));
#863=FACE_BOUND('',#862,.T.);
#864=ADVANCED_FACE('F500',(#863),#847,.F.);
#865=CARTESIAN_POINT('',(304.8,-109.985226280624,0.));
#866=DIRECTION('',(1.,0.,0.));
#867=DIRECTION('',(0.,0.,1.));
#868=AXIS2_PLACEMENT_3D('',#865,#866,#867);
#869=PLANE('',#868);
#870=DIRECTION('',(0.,0.,-1.));
#871=VECTOR('',#870,1.);
#872=CARTESIAN_POINT('',(304.8,45.4676131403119,-31.75));
#873=LINE('',#872,#871);
#874=CARTESIAN_POINT('',(304.8,45.4676131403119,26.2507386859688));
#875=VERTEX_POINT('',#874);
#876=CARTESIAN_POINT('',(304.8,45.4676131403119,-26.2507386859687));
#877=VERTEX_POINT('',#876);
#878=EDGE_CURVE('E248',#875,#877,#873,.T.);
#879=ORIENTED_EDGE('',*,*,#878,.F.);
#880=DIRECTION('',(0.,0.866025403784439,-0.5));
#881=VECTOR('',#880,1.);
#882=CARTESIAN_POINT('',(304.8,50.2301131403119,23.5011080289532));
#883=LINE('',#882,#881);
#884=CARTESIAN_POINT('',(304.8,0.,52.5014773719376));
#885=VERTEX_POINT('',#884);
#886=EDGE_CURVE('E245',#885,#875,#883,.T.);
#887=ORIENTED_EDGE('',*,*,#886,.F.);
#888=DIRECTION('',(0.,0.866025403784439,0.5));
#889=VECTOR('',#888,1.);
#890=CARTESIAN_POINT('',(304.8,4.76250000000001,55.2511080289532));
#891=LINE('',#890,#889);
#892=CARTESIAN_POINT('',(304.8,-45.4676131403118,26.2507386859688));
#893=VERTEX_POINT('',#892);
#894=EDGE_CURVE('E242',#893,#885,#891,.T.);
#895=ORIENTED_EDGE('',*,*,#894,.F.);
#896=DIRECTION('',(0.,0.,1.));
#897=VECTOR('',#896,1.);
#898=CARTESIAN_POINT('',(304.8,-45.4676131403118,31.75));
#899=LINE('',#898,#897);
#900=CARTESIAN_POINT('',(304.8,-45.4676131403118,-26.2507386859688));
#901=VERTEX_POINT('',#900);
#902=EDGE_CURVE('E239',#901,#893,#899,.T.);
#903=ORIENTED_EDGE('',*,*,#902,.F.);
#904=DIRECTION('',(0.,-0.866025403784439,0.5));
#905=VECTOR('',#904,1.);
#906=CARTESIAN_POINT('',(304.8,-50.2301131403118,-23.5011080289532));
#907=LINE('',#906,#905);
#908=CARTESIAN_POINT('',(304.8,0.,-52.5014773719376));
#909=VERTEX_POINT('',#908);
#910=EDGE_CURVE('E233',#909,#901,#907,.T.);
#911=ORIENTED_EDGE('',*,*,#910,.F.);
#912=DIRECTION('',(0.,-0.866025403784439,-0.5));
#913=VECTOR('',#912,1.);
#914=CARTESIAN_POINT('',(304.8,-4.76250000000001,-55.2511080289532));
#915=LINE('',#914,#913);
#916=EDGE_CURVE('E215',#877,#909,#915,.T.);
#917=ORIENTED_EDGE('',*,*,#916,.F.);
#918=EDGE_LOOP('',(#879,#887,#895,#903,#911,#917));
#919=FACE_BOUND('',#918,.T.);
#920=ADVANCED_FACE('F496',(#919),#869,.T.);
#921=CARTESIAN_POINT('',(295.275,0.,63.5));
#922=DIRECTION('',(0.707106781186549,-0.353553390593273,0.612372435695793));
#923=DIRECTION('',(-0.654653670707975,0.,0.755928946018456));
#924=AXIS2_PLACEMENT_3D('',#921,#922,#923);
#925=PLANE('',#924);
#926=DIRECTION('',(0.654653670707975,0.,-0.755928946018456));
#927=VECTOR('',#926,1.);
#928=CARTESIAN_POINT('',(295.275,0.,63.5));
#929=LINE('',#928,#927);
#930=EDGE_CURVE('E301',#885,#800,#929,.F.);
#931=ORIENTED_EDGE('',*,*,#930,.T.);
#932=ORIENTED_EDGE('',*,*,#838,.T.);
#933=DIRECTION('',(0.654653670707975,0.654653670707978,-0.377964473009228));
#934=VECTOR('',#933,1.);
#935=CARTESIAN_POINT('',(295.275,-54.9926131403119,31.75));
#936=LINE('',#935,#934);
#937=EDGE_CURVE('E303',#831,#893,#936,.T.);
#938=ORIENTED_EDGE('',*,*,#937,.T.);
#939=ORIENTED_EDGE('',*,*,#894,.T.);
#940=EDGE_LOOP('',(#931,#932,#938,#939));
#941=FACE_BOUND('',#940,.T.);
#942=ADVANCED_FACE('F499',(#941),#925,.T.);
#943=CARTESIAN_POINT('',(295.275,-54.9926131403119,31.75));
#944=DIRECTION('',(0.707106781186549,-0.707106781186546,0.));
#945=DIRECTION('',(-0.707106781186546,-0.707106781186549,0.));
#946=AXIS2_PLACEMENT_3D('',#943,#944,#945);
#947=PLANE('',#946);
#948=ORIENTED_EDGE('',*,*,#937,.F.);
#949=ORIENTED_EDGE('',*,*,#860,.T.);
#950=DIRECTION('',(0.654653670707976,0.654653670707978,0.377964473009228));
#951=VECTOR('',#950,1.);
#952=CARTESIAN_POINT('',(295.275,-54.9926131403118,-31.75));
#953=LINE('',#952,#951);
#954=EDGE_CURVE('E299',#691,#901,#953,.T.);
#955=ORIENTED_EDGE('',*,*,#954,.T.);
#956=ORIENTED_EDGE('',*,*,#902,.T.);
#957=EDGE_LOOP('',(#948,#949,#955,#956));
#958=FACE_BOUND('',#957,.T.);
#959=ADVANCED_FACE('F532',(#958),#947,.T.);
#960=CARTESIAN_POINT('',(295.275,54.9926131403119,31.75));
#961=DIRECTION('',(0.707106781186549,0.353553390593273,0.612372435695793));
#962=DIRECTION('',(-0.654653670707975,0.,0.755928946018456));
#963=AXIS2_PLACEMENT_3D('',#960,#961,#962);
#964=PLANE('',#963);
#965=ORIENTED_EDGE('',*,*,#930,.F.);
#966=ORIENTED_EDGE('',*,*,#886,.T.);
#967=DIRECTION('',(0.654653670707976,-0.654653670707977,-0.37796447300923));
#968=VECTOR('',#967,1.);
#969=CARTESIAN_POINT('',(295.275,54.9926131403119,31.75));
#970=LINE('',#969,#968);
#971=EDGE_CURVE('E297',#875,#769,#970,.F.);
#972=ORIENTED_EDGE('',*,*,#971,.T.);
#973=ORIENTED_EDGE('',*,*,#807,.T.);
#974=EDGE_LOOP('',(#965,#966,#972,#973));
#975=FACE_BOUND('',#974,.T.);
#976=ADVANCED_FACE('F528',(#975),#964,.T.);
#977=CARTESIAN_POINT('',(295.275,-54.9926131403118,-31.75));
#978=DIRECTION('',(0.707106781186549,-0.353553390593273,-0.612372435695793));
#979=DIRECTION('',(0.654653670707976,0.,0.755928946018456));
#980=AXIS2_PLACEMENT_3D('',#977,#978,#979);
#981=PLANE('',#980);
#982=ORIENTED_EDGE('',*,*,#954,.F.);
#983=ORIENTED_EDGE('',*,*,#714,.T.);
#984=DIRECTION('',(-0.654653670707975,0.,-0.755928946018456));
#985=VECTOR('',#984,1.);
#986=CARTESIAN_POINT('',(310.987175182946,0.,-45.3571428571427));
#987=LINE('',#986,#985);
#988=EDGE_CURVE('E295',#707,#909,#987,.F.);
#989=ORIENTED_EDGE('',*,*,#988,.T.);
#990=ORIENTED_EDGE('',*,*,#910,.T.);
#991=EDGE_LOOP('',(#982,#983,#989,#990));
#992=FACE_BOUND('',#991,.T.);
#993=ADVANCED_FACE('F524',(#992),#981,.T.);
#994=CARTESIAN_POINT('',(295.275,54.9926131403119,-31.75));
#995=DIRECTION('',(0.707106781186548,0.707106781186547,0.));
#996=DIRECTION('',(0.707106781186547,-0.707106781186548,0.));
#997=AXIS2_PLACEMENT_3D('',#994,#995,#996);
#998=PLANE('',#997);
#999=ORIENTED_EDGE('',*,*,#971,.F.);
#1000=ORIENTED_EDGE('',*,*,#878,.T.);
#1001=DIRECTION('',(0.654653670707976,-0.654653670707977,0.37796447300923));
#1002=VECTOR('',#1001,1.);
#1003=CARTESIAN_POINT('',(295.275,54.9926131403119,-31.75));
#1004=LINE('',#1003,#1002);
#1005=EDGE_CURVE('E293',#877,#738,#1004,.F.);
#1006=ORIENTED_EDGE('',*,*,#1005,.T.);
#1007=ORIENTED_EDGE('',*,*,#776,.T.);
#1008=EDGE_LOOP('',(#999,#1000,#1006,#1007));
#1009=FACE_BOUND('',#1008,.T.);
#1010=ADVANCED_FACE('F520',(#1009),#998,.T.);
#1011=CARTESIAN_POINT('',(295.275,0.,-63.5));
#1012=DIRECTION('',(0.70710678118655,0.353553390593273,-0.612372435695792));
#1013=DIRECTION('',(0.654653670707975,0.,0.755928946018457));
#1014=AXIS2_PLACEMENT_3D('',#1011,#1012,#1013);
#1015=PLANE('',#1014);
#1016=ORIENTED_EDGE('',*,*,#988,.F.);
#1017=ORIENTED_EDGE('',*,*,#745,.T.);
#1018=ORIENTED_EDGE('',*,*,#1005,.F.);
#1019=ORIENTED_EDGE('',*,*,#916,.T.);
#1020=EDGE_LOOP('',(#1016,#1017,#1018,#1019));
#1021=FACE_BOUND('',#1020,.T.);
#1022=ADVANCED_FACE('F517',(#1021),#1015,.T.);
#1023=CARTESIAN_POINT('',(228.6,45.4676131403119,0.));
#1024=DIRECTION('',(0.707106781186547,-0.707106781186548,0.));
#1025=DIRECTION('',(-0.707106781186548,-0.707106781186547,0.));
#1026=AXIS2_PLACEMENT_3D('',#1023,#1024,#1025);
#1027=PLANE('',#1026);
#1028=DIRECTION('',(-0.654653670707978,-0.654653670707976,0.377964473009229));
#1029=VECTOR('',#1028,1.);
#1030=CARTESIAN_POINT('',(198.536363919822,15.4039770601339,-8.89349030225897));
#1031=LINE('',#1030,#1029);
#1032=EDGE_CURVE('E193',#730,#648,#1031,.T.);
#1033=ORIENTED_EDGE('',*,*,#1032,.T.);
#1034=ORIENTED_EDGE('',*,*,#649,.T.);
#1035=DIRECTION('',(-0.654653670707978,-0.654653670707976,-0.377964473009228));
#1036=VECTOR('',#1035,1.);
#1037=CARTESIAN_POINT('',(222.104626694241,38.972239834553,22.5006331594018));
#1038=LINE('',#1037,#1036);
#1039=EDGE_CURVE('E204',#640,#761,#1038,.F.);
#1040=ORIENTED_EDGE('',*,*,#1039,.T.);
#1041=ORIENTED_EDGE('',*,*,#762,.T.);
#1042=EDGE_LOOP('',(#1033,#1034,#1040,#1041));
#1043=FACE_BOUND('',#1042,.T.);
#1044=ADVANCED_FACE('F210',(#1043),#1027,.F.);
#1045=CARTESIAN_POINT('',(228.6,-59.7551131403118,87.0011080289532));
#1046=DIRECTION('',(0.707106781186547,-0.353553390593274,-0.612372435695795));
#1047=DIRECTION('',(0.654653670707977,0.,0.755928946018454));
#1048=AXIS2_PLACEMENT_3D('',#1045,#1046,#1047);
#1049=PLANE('',#1048);
#1050=ORIENTED_EDGE('',*,*,#1039,.F.);
#1051=ORIENTED_EDGE('',*,*,#641,.T.);
#1052=DIRECTION('',(-0.654653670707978,0.,-0.755928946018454));
#1053=VECTOR('',#1052,1.);
#1054=CARTESIAN_POINT('',(245.67288946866,0.,72.2155520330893));
#1055=LINE('',#1054,#1053);
#1056=EDGE_CURVE('E205',#630,#792,#1055,.F.);
#1057=ORIENTED_EDGE('',*,*,#1056,.T.);
#1058=ORIENTED_EDGE('',*,*,#793,.T.);
#1059=EDGE_LOOP('',(#1050,#1051,#1057,#1058));
#1060=FACE_BOUND('',#1059,.T.);
#1061=ADVANCED_FACE('F554',(#1060),#1049,.F.);
#1062=CARTESIAN_POINT('',(228.6,-59.7551131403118,-87.0011080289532));
#1063=DIRECTION('',(0.707106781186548,-0.353553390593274,0.612372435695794));
#1064=DIRECTION('',(-0.654653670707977,0.,0.755928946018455));
#1065=AXIS2_PLACEMENT_3D('',#1062,#1063,#1064);
#1066=PLANE('',#1065);
#1067=ORIENTED_EDGE('',*,*,#1032,.F.);
#1068=ORIENTED_EDGE('',*,*,#731,.T.);
#1069=DIRECTION('',(-0.654653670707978,0.,0.755928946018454));
#1070=VECTOR('',#1069,1.);
#1071=CARTESIAN_POINT('',(198.536363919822,0.,-17.7869806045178));
#1072=LINE('',#1071,#1070);
#1073=EDGE_CURVE('E310',#699,#656,#1072,.T.);
#1074=ORIENTED_EDGE('',*,*,#1073,.T.);
#1075=ORIENTED_EDGE('',*,*,#657,.T.);
#1076=EDGE_LOOP('',(#1067,#1068,#1074,#1075));
#1077=FACE_BOUND('',#1076,.T.);
#1078=ADVANCED_FACE('F195',(#1077),#1066,.F.);
#1079=CARTESIAN_POINT('',(228.6,-105.222726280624,-8.2488919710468));
#1080=DIRECTION('',(0.707106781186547,0.353553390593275,-0.612372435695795));
#1081=DIRECTION('',(0.654653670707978,0.,0.755928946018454));
#1082=AXIS2_PLACEMENT_3D('',#1079,#1080,#1081);
#1083=PLANE('',#1082);
#1084=ORIENTED_EDGE('',*,*,#1056,.F.);
#1085=ORIENTED_EDGE('',*,*,#633,.T.);
#1086=DIRECTION('',(-0.654653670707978,0.654653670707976,-0.377964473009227));
#1087=VECTOR('',#1086,1.);
#1088=CARTESIAN_POINT('',(245.672889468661,-62.5405026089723,36.1077760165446));
#1089=LINE('',#1088,#1087);
#1090=EDGE_CURVE('E308',#632,#823,#1089,.F.);
#1091=ORIENTED_EDGE('',*,*,#1090,.T.);
#1092=ORIENTED_EDGE('',*,*,#824,.T.);
#1093=EDGE_LOOP('',(#1084,#1085,#1091,#1092));
#1094=FACE_BOUND('',#1093,.T.);
#1095=ADVANCED_FACE('F547',(#1094),#1083,.F.);
#1096=CARTESIAN_POINT('',(228.6,-105.222726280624,8.24889197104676));
#1097=DIRECTION('',(0.707106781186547,0.353553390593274,0.612372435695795));
#1098=DIRECTION('',(-0.654653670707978,0.,0.755928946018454));
#1099=AXIS2_PLACEMENT_3D('',#1096,#1097,#1098);
#1100=PLANE('',#1099);
#1101=ORIENTED_EDGE('',*,*,#1073,.F.);
#1102=ORIENTED_EDGE('',*,*,#700,.T.);
#1103=DIRECTION('',(0.654653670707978,-0.654653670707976,-0.377964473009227));
#1104=VECTOR('',#1103,1.);
#1105=CARTESIAN_POINT('',(245.672889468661,-62.5405026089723,-36.1077760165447));
#1106=LINE('',#1105,#1104);
#1107=EDGE_CURVE('E306',#689,#664,#1106,.F.);
#1108=ORIENTED_EDGE('',*,*,#1107,.T.);
#1109=ORIENTED_EDGE('',*,*,#665,.T.);
#1110=EDGE_LOOP('',(#1101,#1102,#1108,#1109));
#1111=FACE_BOUND('',#1110,.T.);
#1112=ADVANCED_FACE('F543',(#1111),#1100,.F.);
#1113=CARTESIAN_POINT('',(228.6,-45.4676131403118,0.));
#1114=DIRECTION('',(0.707106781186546,0.707106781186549,0.));
#1115=DIRECTION('',(0.707106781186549,-0.707106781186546,0.));
#1116=AXIS2_PLACEMENT_3D('',#1113,#1114,#1115);
#1117=PLANE('',#1116);
#1118=ORIENTED_EDGE('',*,*,#1090,.F.);
#1119=ORIENTED_EDGE('',*,*,#671,.T.);
#1120=ORIENTED_EDGE('',*,*,#1107,.F.);
#1121=ORIENTED_EDGE('',*,*,#853,.T.);
#1122=EDGE_LOOP('',(#1118,#1119,#1120,#1121));
#1123=FACE_BOUND('',#1122,.T.);
#1124=ADVANCED_FACE('F540',(#1123),#1117,.F.);
#1125=CLOSED_SHELL('',(#85,#125,#156,#187,#218,#249,#271,#327,#349,#366,#383,#400,#417,#429,
#451,#468,#485,#502,#519,#531,#619,#678,#718,#749,#780,#811,#842,#864,#920,#942,#959,#976,#993,
#1010,#1022,#1044,#1061,#1078,#1095,#1112,#1124));
#1126=MANIFOLD_SOLID_BREP('B2',#1125);
#1127=ADVANCED_BREP_SHAPE_REPRESENTATION('',(#18,#1126),#14);
#1128=SHAPE_DEFINITION_REPRESENTATION(#9,#1127);
ENDSEC;
END-ISO-10303-21;
